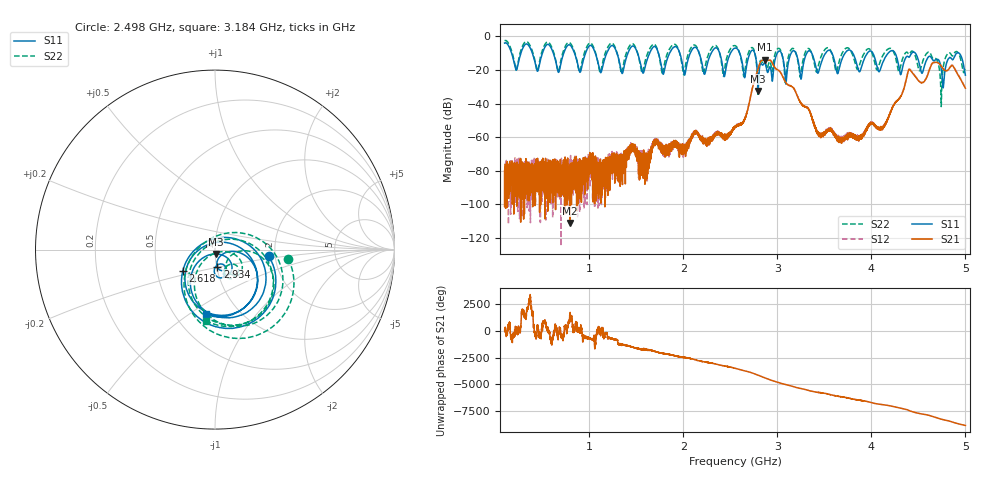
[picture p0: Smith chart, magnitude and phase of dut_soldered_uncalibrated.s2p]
!Keysight Technologies N9917A: A.13.25
!Date: Thursday, 15 October 2026 16:14:31
!Timezone: (UTC-08:00) Pacific Time (US & Canada)
!Model: N9917A
!Serial: MY56072049
!GPS Latitude:
!GPS Longitude:
!GPS TimeStamp: 0001-01-01 00:00:00Z
!GPS Seconds Since Last Read: 0
!CHECKSUM:1733103286
!Correction: S11(Rdy)S21(Rdy)S12(Rdy)S22(Rdy)
!S2P File: Measurements:S11,S21,S12,S22:
# Hz S DB R 50
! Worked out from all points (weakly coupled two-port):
!   10001 points, 100 MHz to 5 GHz, reference 50 ohm
!   highest |S21| = -13.81 dB at 2.869 GHz (marker M1); lowest = -110.9 dB at 795.3 MHz (marker M2)
!   lowest |S11| = -32.4 dB at 2.797 GHz (marker M3), VSWR 1.05, Z = 50.3 - j2.4 ohm
!   |S11| at or under -10 dB: 2.76 GHz to 2.998 GHz (237.7 MHz wide, 8.26 % of centre); 4.254 GHz to 4.428 GHz (174.4 MHz wide, 4.02 % of centre); 4.469 GHz to 4.906 GHz (437.8 MHz wide, 9.34 % of centre) (the widest 3 of 22)
!   |S22| runs from -41.8 to -2.4 dB; largest |S21 - S12| = 0.05
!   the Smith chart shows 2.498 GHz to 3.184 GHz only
!   S11 on the Smith chart (normalised r, x): 2.498 GHz: 1.85, -0.15; 2.618 GHz: 0.68, -0.17; 2.934 GHz: 1.01, -0.20; 3.184 GHz: 0.70, -0.58
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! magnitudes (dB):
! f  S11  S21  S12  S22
! 100 MHz  -4.0  -79.9  -83.1  -2.5
! 446.9 MHz  -20.6  -77.7  -84.0  -20.6
! 566 MHz  -4.8  -79.2  -77.2  -3.4
! 670.9 MHz  -21.2  -83.0  -82.9  -21.4
! 795.3 MHz  -5.1  -110.9  -73.1  -3.9
! 916.8 MHz  -19.0  -98.7  -80.4  -16.8
! 1.007 GHz  -5.4  -73.1  -76.1  -3.9
! 1.116 GHz  -21.1  -77.1  -87.1  -21.7
! 1.232 GHz  -5.6  -75.9  -74.9  -4.0
! 1.734 GHz  -9.5  -63.0  -63.4  -9.5
! 2.498 GHz  -10.4  -58.2  -58.7  -7.7
! 2.55 GHz  -6.9  -54.5  -53.4  -5.5
! 2.618 GHz  -13.3  -52.6  -51.8  -14.4
! 2.797 GHz  -32.4  -19.2  -19.1  -27.3
! 2.869 GHz  -16.0  -13.8  -13.6  -15.0
! 2.934 GHz  -20.3  -14.6  -14.4  -17.5
! 3.184 GHz  -8.8  -31.7  -31.5  -8.0
! 3.367 GHz  -10.0  -48.1  -48.3  -10.2
! 3.682 GHz  -14.3  -60.8  -60.9  -10.8
! 4.184 GHz  -9.6  -47.9  -48.0  -7.3
! 4.408 GHz  -12.0  -19.7  -19.4  -10.2
! 5 GHz  -23.0  -30.8  -30.6  -17.8
